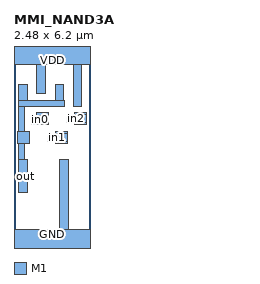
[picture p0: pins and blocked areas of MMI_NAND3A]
MACRO MMI_NAND3A
	CLASS CORE ;
	FOREIGN MMI_NAND3A 0 0 ;
	SIZE 2.48 BY 6.2 ;
	SYMMETRY X Y ;
	SITE CORE1 ;
	PIN out
		DIRECTION output ;
		USE SIGNAL ;
		PORT
			LAYER M1 ;
			RECT 0.16 4.62 0.44 5.13 ;
			LAYER M1 ;
			RECT 1.34 4.62 1.62 5.13 ;
			LAYER M1 ;
			RECT 0.16 4.43 1.64 4.62 ;
			LAYER M1 ;
			RECT 0.16 3.6 0.355 4.43 ;
			LAYER M1 ;
			RECT 0.12 3.22 0.5 3.6 ;
			LAYER M1 ;
			RECT 0.16 2.685 0.355 3.22 ;
			LAYER M1 ;
			RECT 0.16 1.6 0.44 2.685 ;
		END
		AntennaDiffArea 1.099175 ;
	END out
	PIN in1
		DIRECTION input ;
		USE SIGNAL ;
		PORT
			LAYER M1 ;
			RECT 1.36 3.55 1.74 3.6 ;
			LAYER M1 ;
			RECT 1.08 3.27 1.74 3.55 ;
			LAYER M1 ;
			RECT 1.36 3.22 1.74 3.27 ;
		END
		AntennaGateArea 0.28875 ;
	END in1
	PIN GND
		DIRECTION inout ;
		USE GROUND ;
		PORT
			LAYER M1 ;
			RECT 1.49 0.42 1.77 2.685 ;
			LAYER M1 ;
			RECT 0 -0.42 2.48 0.42 ;
		END
	END GND
	PIN in2
		DIRECTION input ;
		USE SIGNAL ;
		PORT
			LAYER M1 ;
			RECT 1.98 4.165 2.36 4.22 ;
			LAYER M1 ;
			RECT 1.71 3.885 2.36 4.165 ;
			LAYER M1 ;
			RECT 1.98 3.84 2.36 3.885 ;
		END
		AntennaGateArea 0.28875 ;
	END in2
	PIN VDD
		DIRECTION inout ;
		USE POWER ;
		PORT
			LAYER M1 ;
			RECT 0 5.78 2.48 6.62 ;
			LAYER M1 ;
			RECT 0.75 4.85 1.03 5.78 ;
			LAYER M1 ;
			RECT 1.93 4.43 2.21 5.78 ;
		END
	END VDD
	PIN in0
		DIRECTION input ;
		USE SIGNAL ;
		PORT
			LAYER M1 ;
			RECT 0.74 4.13 1.12 4.22 ;
			LAYER M1 ;
			RECT 0.575 3.85 1.12 4.13 ;
			LAYER M1 ;
			RECT 0.74 3.84 1.12 3.85 ;
		END
		AntennaGateArea 0.28875 ;
	END in0
	OBS
	END
END MMI_NAND3A
